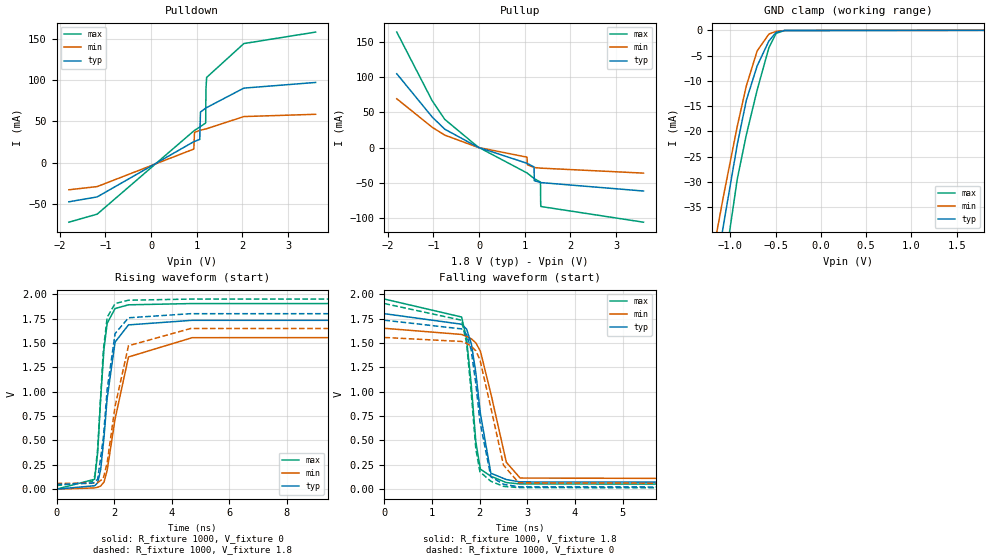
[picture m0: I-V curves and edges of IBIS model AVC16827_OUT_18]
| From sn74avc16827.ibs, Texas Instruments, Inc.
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[Model]   AVC16827_OUT_18
Model_type  3-state
Enable   Active-Low
Vref =   0
Rref =   1000
Cref =   30p
Vmeas =   0.9
| variable   typ   min   max
C_comp   4.21pF   3.37pF   5.59pF
| C_pullup   7.22pF   2.27pF   19.02pF
| C_pulldown   12.28pF   1.01pF   37.25pF
| C_tri-state   4.21pF   3.37pF   5.59pF
[Temperature Range]   40   100   -40
| Ambient temperature   25   85   -40
[Voltage range]   1.8   1.65   1.95
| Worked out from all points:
|   slope of the pulldown table from 0 to 0.27 V, typ, clamps not added: 29.3 ohm
|   slope of the pullup table from 0 to 0.27 V, typ, clamps not added: 42.5 ohm
|   GND clamp passes 1 mA (typ) near -0.53 V on its own axis
|   rising waveform, R_fixture 1000, V_fixture 0: 20-80 % time 350ps typ, 522ps min, 245ps max; typ from 0 V to 1.73 V
|   falling waveform, R_fixture 1000, V_fixture 1.8: 20-80 % time 270ps typ, 428ps min, 219ps max; typ from 1.8 V to 0.048 V
|   rising waveform, R_fixture 1000, V_fixture 1.8: 20-80 % time 337ps typ, 508ps min, 237ps max; typ from 0.048 V to 1.8 V
|   falling waveform, R_fixture 1000, V_fixture 0: 20-80 % time 264ps typ, 400ps min, 209ps max; typ from 1.73 V to 0 V
[GND Clamp]
| AVC16827_OUT_18
|   Voltage   I(typ)   I(min)   I(max)
-1.8V     -124.9mA   -107.3mA   -153mA
-1.245V   -57.64mA   -49.25mA   -71.37mA
-1.17V    -49mA      -41.81mA   -60.87mA
-1.09V    -39.99mA   -34.06mA   -49.94mA
-1.07V    -37.79mA   -32.16mA   -47.27mA
-925mV    -22.63mA   -19.02mA   -29.49mA
-825mV    -13.89mA   -11.03mA   -20.73mA
-705mV    -7.054mA   -4.082mA   -11.83mA
-575mV    -2.111mA   -741uA     -3.443mA
-495mV    -391.5uA   -195.2uA   -599.6uA
-400mV    -32.26uA   -38.14uA   -25.67uA
1.8V      936.6pA    10.73nA    32.16pA
[Pulldown]
| AVC16827_OUT_18
|   Voltage   I(typ)   I(min)   I(max)
-1.8V     -47.42mA   -32.85mA   -72.12mA
-1.18V    -41.51mA   -29mA      -62.38mA
935mV     25.4mA     16.46mA    38.43mA
950mV     25.71mA    36.74mA    38.98mA
1.065V    28.14mA    39.02mA    43.19mA
1.08V     61.15mA    39.25mA    43.74mA
1.19V     65.84mA    40.74mA    47.8mA
1.195V    66.01mA    40.81mA    48.48mA
1.2V      66.17mA    40.88mA    88.03mA
1.215V    66.66mA    41.09mA    103.2mA
2.03V     90.25mA    55.79mA    144.2mA
3.6V      97.11mA    58.56mA    158.1mA
[Pullup]
| AVC16827_OUT_18
|   Voltage   I(typ)   I(min)   I(max)
-1.8V     105mA      69.44mA    164.2mA
-1.025V   43.53mA    28.95mA    66.62mA
-750mV    26.25mA    17.81mA    40.22mA
-20mV     534.9uA    353.3uA    842.4uA
1.05V     -22.2mA    -13.51mA   -35.92mA
1.06V     -22.53mA   -24.37mA   -36.41mA
1.205V    -27.4mA    -28.2mA    -43.79mA
1.21V     -46.91mA   -28.26mA   -44.05mA
1.345V    -49.51mA   -29.08mA   -48.98mA
1.35V     -49.57mA   -29.1mA    -80.34mA
1.355V    -49.64mA   -29.12mA   -83.62mA
3.6V      -61.62mA   -36.17mA   -105.9mA
[Ramp]
| AVC16827_OUT_18
| variable   typ   min   max
dV/dt_r   1.04/3.57E-10   0.93/5.29E-10   1.14/2.46E-10
dV/dt_f   1.05/2.75E-10   0.95/4.34E-10   1.15/2.25E-10
R_load = 1000
[Rising Waveform]
| AVC16827_OUT_18
R_fixture =   1000
C_fixture =   0
L_fixture =   0
V_fixture =   0
V_fixture_min = 0
V_fixture_max = 0
|   Time   V(typ)   V(min)   V(max)
0s        18.29nV    90.61nV    648.3pV
1.325ns   35.26mV    12.82mV    101.8mV
1.43ns    65.96mV    19.72mV    377.6mV
1.535ns   202mV      32.3mV     940.3mV
1.65ns    534.2mV    72.82mV    1.443V
1.76ns    933.5mV    194.2mV    1.702V
2.035ns   1.509V     719.9mV    1.853V
2.5ns     1.685V     1.356V     1.891V
4.715ns   1.732V     1.554V     1.904V
50ns      1.733V     1.556V     1.904V
[Falling Waveform]
| AVC16827_OUT_18
R_fixture =   1000
C_fixture =   0
L_fixture =   0
V_fixture =   1.8
V_fixture_min = 1.65
V_fixture_max = 1.95
|   Time   V(typ)   V(min)   V(max)
0s        1.8V       1.65V      1.95V
1.62ns    1.692V     1.587V     1.766V
1.725ns   1.642V     1.567V     1.542V
1.825ns   1.492V     1.542V     1.062V
1.92ns    1.194V     1.501V     484.1mV
2.015ns   776.4mV    1.415V     205.5mV
2.235ns   163.4mV    980.3mV    132.5mV
2.56ns    98.5mV     275.8mV    67.7mV
2.85ns    74.23mV    114mV      53.36mV
50ns      47.79mV    59.83mV    36.78mV
[Rising Waveform]
| AVC16827_OUT_18
R_fixture =   1000
C_fixture =   0
L_fixture =   0
V_fixture =   1.8
V_fixture_min = 1.65
V_fixture_max = 1.95
|   Time   V(typ)   V(min)   V(max)
0s        47.79mV    59.83mV    36.78mV
1.235ns   61.64mV    60.19mV    77.05mV
1.335ns   73.28mV    63.45mV    139.6mV
1.43ns    103.2mV    67.64mV    417.2mV
1.625ns   521.2mV    109.2mV    1.422V
1.76ns    1.025V     272.8mV    1.763V
2.035ns   1.596V     850.7mV    1.904V
2.5ns     1.758V     1.471V     1.938V
4.66ns    1.8V       1.648V     1.95V
50ns      1.8V       1.65V      1.95V
[Falling Waveform]
| AVC16827_OUT_18
R_fixture =   1000
C_fixture =   0
L_fixture =   0
V_fixture =   0
V_fixture_min = 0
V_fixture_max = 0
|   Time   V(typ)   V(min)   V(max)
0s        1.733V     1.556V     1.904V
1.62ns    1.644V     1.515V     1.733V
1.725ns   1.588V     1.495V     1.5V
1.82ns    1.431V     1.468V     1.003V
1.92ns    1.08V      1.419V     410.8mV
2.005ns   694.1mV    1.329V     178.7mV
2.235ns   126.9mV    835.8mV    80.73mV
2.5ns     50.51mV    247mV      29.07mV
2.82ns    24.05mV    65.38mV    15.96mV
50ns      36.92nV    112.9nV    4.935nV
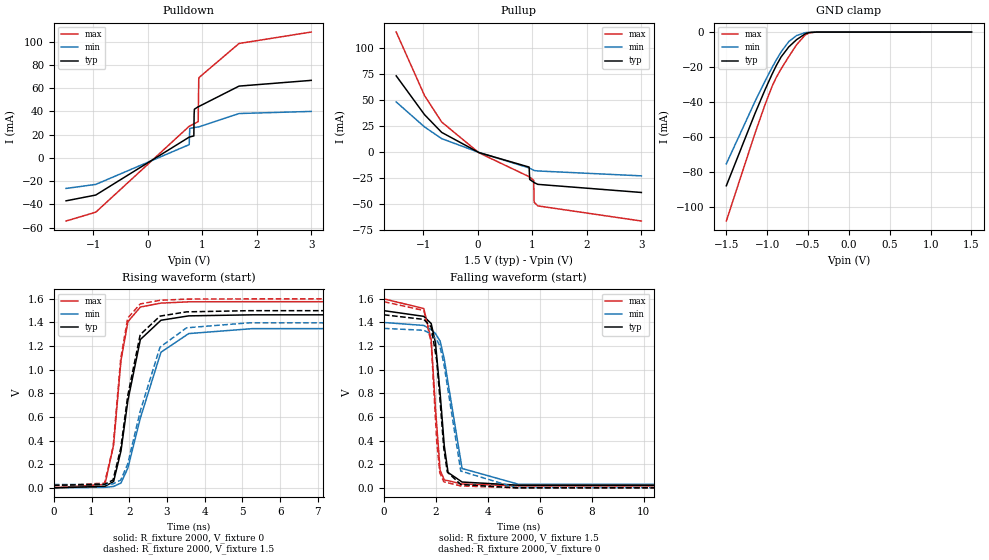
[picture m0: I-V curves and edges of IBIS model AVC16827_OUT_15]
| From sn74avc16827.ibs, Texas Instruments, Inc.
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[Model]   AVC16827_OUT_15
Model_type  3-state
Enable   Active-Low
Vref =   0
Rref =   2000
Cref =   15p
Vmeas =   0.75
| variable   typ   min   max
C_comp   4.15pF   3.37pF   5.47pF
| C_pullup   5.54pF   0.13pF   14.08pF
| C_pulldown   8.37pF   0.12pF   29.77pF
| C_tri-state   4.15pF   3.37pF   5.47pF
[Temperature Range]   40   100   -40
| Ambient temperature   25   85   -40
[Voltage range]   1.5   1.4   1.6
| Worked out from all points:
|   slope of the pulldown table from 0 to 0.225 V, typ, clamps not added: 32 ohm
|   slope of the pullup table from 0 to 0.225 V, typ, clamps not added: 53.5 ohm
|   GND clamp passes 1 mA (typ) near -0.53 V on its own axis
|   rising waveform, R_fixture 2000, V_fixture 0: 20-80 % time 435ps typ, 663ps min, 290ps max; typ from 0 V to 1.47 V
|   falling waveform, R_fixture 2000, V_fixture 1.5: 20-80 % time 344ps typ, 559ps min, 264ps max; typ from 1.5 V to 0.022 V
|   rising waveform, R_fixture 2000, V_fixture 1.5: 20-80 % time 429ps typ, 664ps min, 286ps max; typ from 0.022 V to 1.5 V
|   falling waveform, R_fixture 2000, V_fixture 0: 20-80 % time 337ps typ, 526ps min, 252ps max; typ from 1.47 V to 0 V
[GND Clamp]
| AVC16827_OUT_15
|   Voltage   I(typ)   I(min)   I(max)
-1.5V     -88.01mA   -75.43mA   -108.2mA
-1.15V    -46.72mA   -39.85mA   -58.1mA
-1.025V   -32.91mA   -27.95mA   -41.39mA
-940mV    -24.11mA   -20.31mA   -31.1mA
-890mV    -19.32mA   -16.08mA   -26.07mA
-830mV    -14.27mA   -11.39mA   -21.12mA
-735mV    -8.467mA   -5.433mA   -14.02mA
-640mV    -4.344mA   -1.993mA   -7.258mA
-535mV    -1.059mA   -358.9uA   -1.71mA
-485mV    -308.8uA   -165.9uA   -442.3uA
-395mV    -28.16uA   -34.51uA   -21.38uA
1.5V      920.5pA    10.07nA    29.12pA
[Pulldown]
| AVC16827_OUT_15
|   Voltage   I(typ)   I(min)   I(max)
-1.5V     -36.97mA   -26.32mA   -54.33mA
-955mV    -31.99mA   -22.84mA   -46.74mA
760mV     17.82mA    11.36mA    27.17mA
770mV     17.93mA    25.25mA    27.4mA
845mV     18.87mA    26.05mA    29.17mA
850mV     37.09mA    26.08mA    29.29mA
855mV     41.82mA    26.11mA    29.41mA
925mV     43.93mA    26.57mA    31.16mA
935mV     44.14mA    26.65mA    67.28mA
940mV     44.24mA    26.69mA    69.07mA
1.675V    61.7mA     38.11mA    98.36mA
3V        66.63mA    39.93mA    108.2mA
[Pullup]
| AVC16827_OUT_15
|   Voltage   I(typ)   I(min)   I(max)
-1.5V     73.31mA    48.24mA    115.4mA
-980mV    35.99mA    24.21mA    54.34mA
-665mV    18.97mA    12.97mA    28.92mA
20mV      -420.5uA   -275.9uA   -662.9uA
940mV     -14.35mA   -15.15mA   -23.58mA
950mV     -26.22mA   -15.4mA    -23.99mA
1.02V     -28.75mA   -17.27mA   -26.94mA
1.025V    -28.95mA   -17.41mA   -27.17mA
1.03V     -29.14mA   -17.56mA   -46.58mA
1.035V    -29.33mA   -17.7mA    -48.24mA
1.1V      -30.94mA   -18.07mA   -51.63mA
3V        -38.73mA   -22.77mA   -66.15mA
[Ramp]
| AVC16827_OUT_15
| variable   typ   min   max
dV/dt_r   0.88/4.39E-10   0.81/6.70E-10   0.95/2.99E-10
dV/dt_f   0.89/3.53E-10   0.82/5.61E-10   0.95/2.73E-10
R_load = 2000
[Rising Waveform]
| AVC16827_OUT_15
R_fixture =   2000
C_fixture =   0
L_fixture =   0
V_fixture =   0
V_fixture_min = 0
V_fixture_max = 0
|   Time   V(typ)   V(min)   V(max)
0s        17.56nV    94.06nV    547.9pV
1.355ns   13.11mV    4.388mV    29.68mV
1.585ns   53.68mV    12.11mV    364.2mV
1.78ns    311.5mV    40.68mV    1.077V
1.965ns   741.2mV    169.3mV    1.407V
2.295ns   1.256V     591.7mV    1.531V
2.84ns    1.419V     1.148V     1.564V
3.575ns   1.456V     1.306V     1.575V
5.265ns   1.465V     1.348V     1.576V
50ns      1.465V     1.35V      1.576V
[Falling Waveform]
| AVC16827_OUT_15
R_fixture =   2000
C_fixture =   0
L_fixture =   0
V_fixture =   1.5
V_fixture_min = 1.4
V_fixture_max = 1.6
|   Time   V(typ)   V(min)   V(max)
0s        1.5V       1.4V       1.6V
1.535ns   1.452V     1.375V     1.518V
1.82ns    1.391V     1.339V     1.256V
1.985ns   1.228V     1.306V     669.1mV
2.165ns   800.1mV    1.242V     148.7mV
2.325ns   354.7mV    1.089V     66.55mV
2.47ns    129.9mV    888.4mV    60.53mV
3.01ns    49.36mV    164mV      32.72mV
5.195ns   22.1mV     29.69mV    16.54mV
50ns      21.56mV    27.72mV    16.25mV
[Rising Waveform]
| AVC16827_OUT_15
R_fixture =   2000
C_fixture =   0
L_fixture =   0
V_fixture =   1.5
V_fixture_min = 1.4
V_fixture_max = 1.6
|   Time   V(typ)   V(min)   V(max)
0s        21.56mV    27.72mV    16.25mV
1.345ns   30.04mV    29.29mV    40.27mV
1.57ns    66.49mV    33.74mV    342.4mV
1.775ns   337.3mV    65.47mV    1.098V
1.96ns    780.8mV    203.8mV    1.438V
2.29ns    1.297V     647.8mV    1.557V
2.815ns   1.454V     1.191V     1.588V
3.52ns    1.49V      1.355V     1.598V
5.165ns   1.5V       1.397V     1.6V
50ns      1.5V       1.4V       1.6V
[Falling Waveform]
| AVC16827_OUT_15
R_fixture =   2000
C_fixture =   0
L_fixture =   0
V_fixture =   0
V_fixture_min = 0
V_fixture_max = 0
|   Time   V(typ)   V(min)   V(max)
0s        1.465V     1.35V      1.576V
1.54ns    1.426V     1.334V     1.501V
1.82ns    1.362V     1.301V     1.23V
2.035ns   1.075V     1.252V     388.4mV
2.15ns    771.2mV    1.204V     130.1mV
2.305ns   336.4mV    1.055V     51.34mV
2.44ns    134.2mV    866.6mV    44.19mV
2.96ns    28.17mV    142mV      16.19mV
5.075ns   451.3uV    1.994mV    298.2uV
50ns      42.13nV    123.5nV    4.587nV
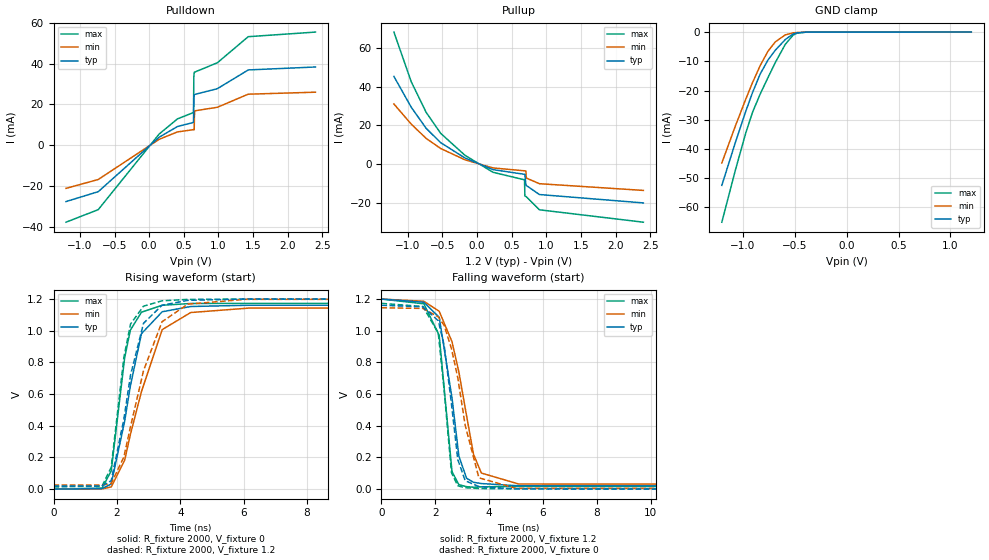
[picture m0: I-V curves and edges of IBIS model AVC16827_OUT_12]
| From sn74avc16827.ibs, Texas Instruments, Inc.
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[Model]   AVC16827_OUT_12
Model_type  3-state
Enable   Active-Low
Vref =   0
Rref =   2000
Cref =   15p
Vmeas =   0.6
| variable   typ   min   max
C_comp   3.95pF   3.28pF   4.86pF
| C_pullup   2.84pF   0.14pF   6.87pF
| C_pulldown   4.95pF   1.09pF   13.32pF
| C_tri-state   3.95pF   3.28pF   4.86pF
[Temperature Range]   40   100   -40
| Ambient temperature   25   85   -40
[Voltage range]   1.2   1.2   1.2
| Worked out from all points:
|   slope of the pulldown table from 0 to 0.18 V, typ, clamps not added: 37.4 ohm
|   slope of the pullup table from 0 to 0.18 V, typ, clamps not added: 76 ohm
|   GND clamp passes 1 mA (typ) near -0.53 V on its own axis
|   rising waveform, R_fixture 2000, V_fixture 0: 20-80 % time 605ps typ, 894ps min, 423ps max; typ from 0 V to 1.16 V
|   falling waveform, R_fixture 2000, V_fixture 1.2: 20-80 % time 508ps typ, 796ps min, 373ps max; typ from 1.2 V to 0.02 V
|   rising waveform, R_fixture 2000, V_fixture 1.2: 20-80 % time 610ps typ, 883ps min, 423ps max; typ from 0.02 V to 1.2 V
|   falling waveform, R_fixture 2000, V_fixture 0: 20-80 % time 482ps typ, 721ps min, 360ps max; typ from 1.16 V to 0 V
[GND Clamp]
| AVC16827_OUT_12
|   Voltage   I(typ)   I(min)   I(max)
-1.2V     -52.43mA   -44.77mA   -65.04mA
-1.07V    -37.79mA   -32.16mA   -47.27mA
-970mV    -27.13mA   -22.95mA   -34.56mA
-905mV    -20.72mA   -17.32mA   -27.47mA
-830mV    -14.27mA   -11.39mA   -21.12mA
-755mV    -9.488mA   -6.488mA   -15.49mA
-685mV    -6.173mA   -3.328mA   -10.39mA
-590mV    -2.576mA   -964.7uA   -4.226mA
-515mV    -666uA     -274.7uA   -1.066mA
-475mV    -256.4uA   -142.9uA   -341.2uA
-390mV    -24.57uA   -31.16uA   -17.8uA
1.2V      903.8pA    3.995nA    28.94pA
[Pulldown]
| AVC16827_OUT_12
|   Voltage   I(typ)   I(min)   I(max)
-1.2V     -27.61mA   -21.14mA   -37.72mA
-735mV    -22.76mA   -16.79mA   -31.57mA
145mV     3.97mA     2.919mA    5.519mA
410mV     9.201mA    6.562mA    12.97mA
640mV     11.19mA    7.644mA    16.03mA
645mV     21.65mA    7.645mA    33.6mA
650mV     24.75mA    7.66mA     35.76mA
655mV     24.9mA     16.56mA    35.84mA
660mV     24.94mA    16.89mA    35.9mA
985mV     27.75mA    18.63mA    40.46mA
1.43V     36.93mA    25.04mA    53.24mA
2.4V      38.38mA    26.02mA    55.49mA
[Pullup]
| AVC16827_OUT_12
|   Voltage   I(typ)   I(min)   I(max)
-1.2V     45.42mA    31.11mA    68.39mA
-950mV    29.44mA    20.7mA     42.65mA
-735mV    18.52mA    13.29mA    26.81mA
-525mV    11.07mA    8.049mA    15.91mA
-175mV    3.147mA    2.201mA    4.531mA
230mV     -2.893mA   -2.023mA   -4.269mA
685mV     -5.328mA   -3.511mA   -8.179mA
690mV     -5.367mA   -3.522mA   -16.51mA
705mV     -11.02mA   -3.556mA   -16.81mA
710mV     -11.09mA   -7.24mA    -16.92mA
900mV     -15.81mA   -10.2mA    -23.72mA
2.4V      -20.15mA   -13.67mA   -30.14mA
[Ramp]
| AVC16827_OUT_12
| variable   typ   min   max
dV/dt_r   0.70/6.13E-10   0.69/8.97E-10   0.70/4.30E-10
dV/dt_f   0.71/5.13E-10   0.70/7.97E-10   0.71/3.78E-10
R_load = 2000
[Rising Waveform]
| AVC16827_OUT_12
R_fixture =   2000
C_fixture =   0
L_fixture =   0
V_fixture =   0
V_fixture_min = 0
V_fixture_max = 0
|   Time   V(typ)   V(min)   V(max)
0s        17.51nV    99.06nV    468.2pV
1.53ns    3.659mV    1.657mV    6.8mV
1.82ns    32.58mV    13.89mV    114.1mV
2.245ns   429.1mV    183.1mV    829mV
2.425ns   651.1mV    344.8mV    1.004V
2.775ns   981.4mV    615.7mV    1.117V
3.43ns    1.12V      1.007V     1.161V
4.33ns    1.153V     1.115V     1.172V
6.155ns   1.161V     1.143V     1.173V
50ns      1.161V     1.145V     1.173V
[Falling Waveform]
| AVC16827_OUT_12
R_fixture =   2000
C_fixture =   0
L_fixture =   0
V_fixture =   1.2
V_fixture_min = 1.2
V_fixture_max = 1.2
|   Time   V(typ)   V(min)   V(max)
0s        1.2V       1.2V       1.2V
1.575ns   1.18V      1.186V     1.17V
2.145ns   1.085V     1.123V     970.7mV
2.62ns    576.1mV    930.6mV    110.8mV
2.875ns   209.5mV    740.5mV    28.39mV
3.16ns    69.15mV    464.4mV    15.74mV
3.42ns    43.29mV    220.1mV    12.1mV
3.71ns    35.39mV    101.7mV    14.96mV
5.095ns   21.27mV    32.62mV    16.97mV
50ns      19.64mV    26.43mV    14.18mV
[Rising Waveform]
| AVC16827_OUT_12
R_fixture =   2000
C_fixture =   0
L_fixture =   0
V_fixture =   1.2
V_fixture_min = 1.2
V_fixture_max = 1.2
|   Time   V(typ)   V(min)   V(max)
0s        19.64mV    26.43mV    14.18mV
1.53ns    20.59mV    25.41mV    18.92mV
1.82ns    53.22mV    36.11mV    137.8mV
2.22ns    442.9mV    203.7mV    832.1mV
2.43ns    720mV      395.4mV    1.042V
2.84ns    1.047V     747.8mV    1.155V
3.425ns   1.161V     1.057V     1.189V
4.24ns    1.192V     1.168V     1.198V
6.05ns    1.2V       1.198V     1.2V
50ns      1.2V       1.2V       1.2V
[Falling Waveform]
| AVC16827_OUT_12
R_fixture =   2000
C_fixture =   0
L_fixture =   0
V_fixture =   0
V_fixture_min = 0
V_fixture_max = 0
|   Time   V(typ)   V(min)   V(max)
0s        1.161V     1.145V     1.173V
1.54ns    1.151V     1.141V     1.153V
2.11ns    1.063V     1.088V     985.4mV
2.33ns    907.8mV    1.033V     621.7mV
2.6ns     537.7mV    886.6mV    104.4mV
2.835ns   187.4mV    703.2mV    21.16mV
3.11ns    53.32mV    402.9mV    8.975mV
3.62ns    16.43mV    71.45mV    3.944mV
4.99ns    1.367mV    5.541mV    2.788mV
50ns      41.01nV    -52.79nV   24.04nV
